VERSION 5.7 ;
  NOWIREEXTENSIONATPIN ON ;
  DIVIDERCHAR "/" ;
  BUSBITCHARS "[]" ;
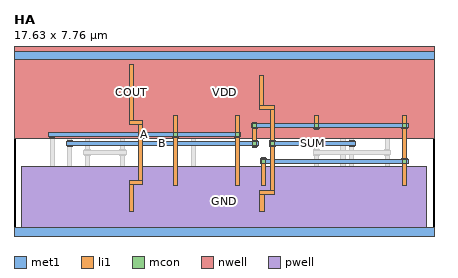
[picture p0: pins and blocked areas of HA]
MACRO HA
  CLASS CORE ;
  FOREIGN HA ;
  ORIGIN 0.000 0.000 ;
  SIZE 17.630 BY 7.760 ;
  SYMMETRY X Y ;
  SITE unitrh ;
  PIN SUM
    DIRECTION OUTPUT ;
    USE SIGNAL ;
    ANTENNADIFFAREA 1.543800 ;
    PORT
      LAYER met1 ;
        RECT 10.735 3.965 10.965 3.995 ;
        RECT 14.065 3.965 14.295 3.995 ;
        RECT 10.705 3.795 14.325 3.965 ;
        RECT 10.735 3.765 10.965 3.795 ;
        RECT 14.065 3.765 14.295 3.795 ;
    END
    PORT
      LAYER li1 ;
        RECT 10.285 5.470 10.455 6.740 ;
        RECT 10.285 5.300 10.935 5.470 ;
        RECT 10.765 1.920 10.935 5.300 ;
        RECT 10.325 1.750 10.935 1.920 ;
        RECT 10.325 1.020 10.495 1.750 ;
      LAYER mcon ;
        RECT 10.765 3.795 10.935 3.965 ;
    END
  END SUM
  PIN COUT
    DIRECTION OUTPUT ;
    USE SIGNAL ;
    ANTENNADIFFAREA 0.771900 ;
    PORT
      LAYER li1 ;
        RECT 4.850 4.845 5.020 7.200 ;
        RECT 4.850 4.675 5.385 4.845 ;
        RECT 5.215 2.345 5.385 4.675 ;
        RECT 4.845 2.175 5.385 2.345 ;
        RECT 4.845 1.020 5.015 2.175 ;
    END
  END COUT
  PIN A
    DIRECTION INPUT ;
    USE SIGNAL ;
    ANTENNAGATEAREA 3.093750 ;
    PORT
      LAYER met1 ;
        RECT 1.485 4.335 1.715 4.365 ;
        RECT 6.665 4.335 6.895 4.365 ;
        RECT 9.255 4.335 9.485 4.365 ;
        RECT 1.455 4.165 9.515 4.335 ;
        RECT 1.485 4.135 1.715 4.165 ;
        RECT 6.665 4.135 6.895 4.165 ;
        RECT 9.255 4.135 9.485 4.165 ;
    END
    PORT
      LAYER li1 ;
        RECT 6.695 2.100 6.865 5.045 ;
      LAYER mcon ;
        RECT 6.695 4.165 6.865 4.335 ;
    END
    PORT
      LAYER li1 ;
        RECT 9.285 2.100 9.455 5.045 ;
      LAYER mcon ;
        RECT 9.285 4.165 9.455 4.335 ;
    END
  END A
  PIN B
    DIRECTION INPUT ;
    USE SIGNAL ;
    ANTENNAGATEAREA 3.081750 ;
    PORT
      LAYER met1 ;
        RECT 9.995 4.705 10.225 4.735 ;
        RECT 12.585 4.705 12.815 4.735 ;
        RECT 16.285 4.705 16.515 4.735 ;
        RECT 9.965 4.535 16.545 4.705 ;
        RECT 9.995 4.505 10.225 4.535 ;
        RECT 12.585 4.505 12.815 4.535 ;
        RECT 16.285 4.505 16.515 4.535 ;
        RECT 2.225 3.965 2.455 3.995 ;
        RECT 9.995 3.965 10.225 3.995 ;
        RECT 2.195 3.795 10.255 3.965 ;
        RECT 2.225 3.765 2.455 3.795 ;
        RECT 9.995 3.765 10.225 3.795 ;
        RECT 10.365 3.225 10.595 3.255 ;
        RECT 16.285 3.225 16.515 3.255 ;
        RECT 10.335 3.055 16.545 3.225 ;
        RECT 10.365 3.025 10.595 3.055 ;
        RECT 16.285 3.025 16.515 3.055 ;
    END
    PORT
      LAYER li1 ;
        RECT 10.025 3.715 10.195 4.785 ;
      LAYER mcon ;
        RECT 10.025 4.535 10.195 4.705 ;
        RECT 10.025 3.795 10.195 3.965 ;
    END
    PORT
      LAYER li1 ;
        RECT 10.395 2.100 10.565 3.305 ;
      LAYER mcon ;
        RECT 10.395 3.055 10.565 3.225 ;
    END
    PORT
      LAYER li1 ;
        RECT 16.315 2.100 16.485 5.045 ;
      LAYER mcon ;
        RECT 16.315 4.535 16.485 4.705 ;
        RECT 16.315 3.055 16.485 3.225 ;
    END
    PORT
      LAYER li1 ;
        RECT 12.615 4.455 12.785 5.045 ;
      LAYER mcon ;
        RECT 12.615 4.535 12.785 4.705 ;
    END
  END B
  PIN VDD
    DIRECTION INOUT ;
    USE POWER ;
    SHAPE ABUTMENT ;
    PORT
      LAYER nwell ;
        RECT 0.000 4.110 17.630 7.940 ;
      LAYER met1 ;
        RECT 0.000 7.410 17.630 7.760 ;
    END
  END VDD
  PIN GND
    DIRECTION INOUT ;
    USE GROUND ;
    SHAPE ABUTMENT ;
    PORT
      LAYER pwell ;
        RECT 0.320 0.000 17.310 2.900 ;
      LAYER met1 ;
        RECT 0.000 0.000 17.630 0.350 ;
    END
  END GND
  OBS
      LAYER li1 ;
        RECT 0.000 7.410 17.630 7.760 ;
        RECT 0.320 4.290 0.660 7.410 ;
        RECT 1.195 5.315 1.365 7.410 ;
        RECT 1.635 5.465 1.805 7.200 ;
        RECT 2.075 5.735 2.245 7.410 ;
        RECT 2.515 5.465 2.685 7.200 ;
        RECT 2.955 5.735 3.125 7.410 ;
        RECT 1.635 5.295 3.165 5.465 ;
        RECT 0.320 0.350 0.660 2.900 ;
        RECT 1.515 2.095 1.685 5.045 ;
        RECT 2.285 4.890 2.455 5.045 ;
        RECT 2.255 4.715 2.455 4.890 ;
        RECT 2.255 2.095 2.425 4.715 ;
        RECT 1.100 1.845 1.270 1.925 ;
        RECT 2.070 1.845 2.240 1.925 ;
        RECT 2.995 1.920 3.165 5.295 ;
        RECT 3.650 4.290 3.990 7.410 ;
        RECT 4.410 5.365 4.580 7.410 ;
        RECT 5.290 5.365 5.460 7.410 ;
        RECT 1.100 1.675 2.240 1.845 ;
        RECT 1.100 0.545 1.270 1.675 ;
        RECT 1.585 0.350 1.755 1.300 ;
        RECT 2.070 0.795 2.240 1.675 ;
        RECT 2.555 1.750 3.165 1.920 ;
        RECT 2.555 1.015 2.725 1.750 ;
        RECT 3.040 0.795 3.210 1.565 ;
        RECT 2.070 0.625 3.210 0.795 ;
        RECT 2.070 0.545 2.240 0.625 ;
        RECT 3.040 0.545 3.210 0.625 ;
        RECT 3.650 0.350 3.990 2.900 ;
        RECT 4.475 2.100 4.645 5.045 ;
        RECT 5.870 4.290 6.210 7.410 ;
        RECT 6.630 5.365 6.800 7.410 ;
        RECT 7.070 4.845 7.240 7.200 ;
        RECT 7.510 5.365 7.680 7.410 ;
        RECT 7.070 4.675 7.605 4.845 ;
        RECT 4.365 0.800 4.535 1.930 ;
        RECT 5.335 0.800 5.505 1.930 ;
        RECT 4.365 0.630 5.505 0.800 ;
        RECT 4.365 0.350 4.535 0.630 ;
        RECT 4.850 0.350 5.020 0.630 ;
        RECT 5.335 0.350 5.505 0.630 ;
        RECT 5.870 0.350 6.210 2.900 ;
        RECT 7.435 2.345 7.605 4.675 ;
        RECT 8.090 4.290 8.430 7.410 ;
        RECT 8.965 5.470 9.135 7.080 ;
        RECT 9.405 5.730 9.575 7.410 ;
        RECT 9.845 7.000 10.895 7.170 ;
        RECT 9.845 5.470 10.015 7.000 ;
        RECT 10.725 5.730 10.895 7.000 ;
        RECT 8.965 5.300 10.015 5.470 ;
        RECT 10.395 4.085 10.565 5.045 ;
        RECT 11.420 4.290 11.760 7.410 ;
        RECT 12.295 5.470 12.465 7.080 ;
        RECT 12.735 5.730 12.905 7.410 ;
        RECT 13.175 7.000 14.225 7.170 ;
        RECT 13.175 5.470 13.345 7.000 ;
        RECT 12.295 5.300 13.345 5.470 ;
        RECT 13.615 5.470 13.785 6.740 ;
        RECT 14.055 5.730 14.225 7.000 ;
        RECT 13.615 5.300 14.265 5.470 ;
        RECT 7.065 2.175 7.605 2.345 ;
        RECT 6.585 0.800 6.755 1.930 ;
        RECT 7.065 1.020 7.235 2.175 ;
        RECT 7.555 0.800 7.725 1.930 ;
        RECT 6.585 0.630 7.725 0.800 ;
        RECT 6.585 0.350 6.755 0.630 ;
        RECT 7.070 0.350 7.240 0.630 ;
        RECT 7.555 0.350 7.725 0.630 ;
        RECT 8.090 0.350 8.430 2.900 ;
        RECT 8.870 1.850 9.040 1.930 ;
        RECT 9.840 1.850 10.010 1.930 ;
        RECT 8.870 1.680 10.010 1.850 ;
        RECT 8.870 0.550 9.040 1.680 ;
        RECT 9.355 0.350 9.525 1.305 ;
        RECT 9.840 0.800 10.010 1.680 ;
        RECT 10.810 0.800 10.980 1.570 ;
        RECT 9.840 0.630 10.980 0.800 ;
        RECT 9.840 0.550 10.010 0.630 ;
        RECT 10.810 0.550 10.980 0.630 ;
        RECT 11.420 0.350 11.760 2.900 ;
        RECT 12.615 2.100 12.785 3.675 ;
        RECT 13.725 2.100 13.895 5.045 ;
        RECT 12.200 1.850 12.370 1.930 ;
        RECT 13.170 1.850 13.340 1.930 ;
        RECT 14.095 1.920 14.265 5.300 ;
        RECT 14.750 4.290 15.090 7.410 ;
        RECT 15.500 5.365 15.670 7.410 ;
        RECT 15.940 4.845 16.110 7.200 ;
        RECT 16.380 5.365 16.550 7.410 ;
        RECT 15.575 4.675 16.110 4.845 ;
        RECT 12.200 1.680 13.340 1.850 ;
        RECT 12.200 0.550 12.370 1.680 ;
        RECT 12.685 0.350 12.855 1.305 ;
        RECT 13.170 0.800 13.340 1.680 ;
        RECT 13.655 1.750 14.265 1.920 ;
        RECT 13.655 1.020 13.825 1.750 ;
        RECT 14.140 0.800 14.310 1.570 ;
        RECT 13.170 0.630 14.310 0.800 ;
        RECT 13.170 0.550 13.340 0.630 ;
        RECT 14.140 0.550 14.310 0.630 ;
        RECT 14.750 0.350 15.090 2.900 ;
        RECT 15.575 2.345 15.745 4.675 ;
        RECT 16.970 4.290 17.310 7.410 ;
        RECT 15.575 2.175 16.115 2.345 ;
        RECT 15.455 0.800 15.625 1.930 ;
        RECT 15.945 1.020 16.115 2.175 ;
        RECT 16.425 0.800 16.595 1.930 ;
        RECT 15.455 0.630 16.595 0.800 ;
        RECT 15.455 0.350 15.625 0.630 ;
        RECT 15.940 0.350 16.110 0.630 ;
        RECT 16.425 0.350 16.595 0.630 ;
        RECT 16.970 0.350 17.310 2.900 ;
        RECT 0.000 0.000 17.630 0.350 ;
      LAYER mcon ;
        RECT 0.775 7.495 0.945 7.665 ;
        RECT 1.145 7.495 1.315 7.665 ;
        RECT 1.515 7.495 1.685 7.665 ;
        RECT 1.885 7.495 2.055 7.665 ;
        RECT 2.255 7.495 2.425 7.665 ;
        RECT 2.625 7.495 2.795 7.665 ;
        RECT 2.995 7.495 3.165 7.665 ;
        RECT 3.365 7.495 3.535 7.665 ;
        RECT 4.105 7.495 4.275 7.665 ;
        RECT 4.475 7.495 4.645 7.665 ;
        RECT 4.845 7.495 5.015 7.665 ;
        RECT 5.215 7.495 5.385 7.665 ;
        RECT 5.585 7.495 5.755 7.665 ;
        RECT 6.325 7.495 6.495 7.665 ;
        RECT 6.695 7.495 6.865 7.665 ;
        RECT 7.065 7.495 7.235 7.665 ;
        RECT 7.435 7.495 7.605 7.665 ;
        RECT 7.805 7.495 7.975 7.665 ;
        RECT 8.545 7.495 8.715 7.665 ;
        RECT 8.915 7.495 9.085 7.665 ;
        RECT 9.285 7.495 9.455 7.665 ;
        RECT 9.655 7.495 9.825 7.665 ;
        RECT 10.025 7.495 10.195 7.665 ;
        RECT 10.395 7.495 10.565 7.665 ;
        RECT 10.765 7.495 10.935 7.665 ;
        RECT 11.135 7.495 11.305 7.665 ;
        RECT 11.875 7.495 12.045 7.665 ;
        RECT 12.245 7.495 12.415 7.665 ;
        RECT 12.615 7.495 12.785 7.665 ;
        RECT 12.985 7.495 13.155 7.665 ;
        RECT 13.355 7.495 13.525 7.665 ;
        RECT 13.725 7.495 13.895 7.665 ;
        RECT 14.095 7.495 14.265 7.665 ;
        RECT 14.465 7.495 14.635 7.665 ;
        RECT 15.205 7.495 15.375 7.665 ;
        RECT 15.575 7.495 15.745 7.665 ;
        RECT 15.945 7.495 16.115 7.665 ;
        RECT 16.315 7.495 16.485 7.665 ;
        RECT 16.685 7.495 16.855 7.665 ;
        RECT 1.515 4.165 1.685 4.335 ;
        RECT 2.255 3.795 2.425 3.965 ;
        RECT 2.995 3.425 3.165 3.595 ;
        RECT 4.475 3.425 4.645 3.595 ;
        RECT 10.395 4.165 10.565 4.335 ;
        RECT 12.615 3.425 12.785 3.595 ;
        RECT 7.435 2.685 7.605 2.855 ;
        RECT 13.725 2.685 13.895 2.855 ;
        RECT 14.095 3.795 14.265 3.965 ;
        RECT 15.575 4.165 15.745 4.335 ;
        RECT 15.575 3.425 15.745 3.595 ;
        RECT 0.775 0.095 0.945 0.265 ;
        RECT 1.145 0.095 1.315 0.265 ;
        RECT 1.515 0.095 1.685 0.265 ;
        RECT 1.885 0.095 2.055 0.265 ;
        RECT 2.255 0.095 2.425 0.265 ;
        RECT 2.625 0.095 2.795 0.265 ;
        RECT 2.995 0.095 3.165 0.265 ;
        RECT 3.365 0.095 3.535 0.265 ;
        RECT 4.105 0.095 4.275 0.265 ;
        RECT 4.475 0.095 4.645 0.265 ;
        RECT 4.845 0.095 5.015 0.265 ;
        RECT 5.215 0.095 5.385 0.265 ;
        RECT 5.585 0.095 5.755 0.265 ;
        RECT 6.325 0.095 6.495 0.265 ;
        RECT 6.695 0.095 6.865 0.265 ;
        RECT 7.065 0.095 7.235 0.265 ;
        RECT 7.435 0.095 7.605 0.265 ;
        RECT 7.805 0.095 7.975 0.265 ;
        RECT 8.545 0.095 8.715 0.265 ;
        RECT 8.915 0.095 9.085 0.265 ;
        RECT 9.285 0.095 9.455 0.265 ;
        RECT 9.655 0.095 9.825 0.265 ;
        RECT 10.025 0.095 10.195 0.265 ;
        RECT 10.395 0.095 10.565 0.265 ;
        RECT 10.765 0.095 10.935 0.265 ;
        RECT 11.135 0.095 11.305 0.265 ;
        RECT 11.875 0.095 12.045 0.265 ;
        RECT 12.245 0.095 12.415 0.265 ;
        RECT 12.615 0.095 12.785 0.265 ;
        RECT 12.985 0.095 13.155 0.265 ;
        RECT 13.355 0.095 13.525 0.265 ;
        RECT 13.725 0.095 13.895 0.265 ;
        RECT 14.095 0.095 14.265 0.265 ;
        RECT 14.465 0.095 14.635 0.265 ;
        RECT 15.205 0.095 15.375 0.265 ;
        RECT 15.575 0.095 15.745 0.265 ;
        RECT 15.945 0.095 16.115 0.265 ;
        RECT 16.315 0.095 16.485 0.265 ;
        RECT 16.685 0.095 16.855 0.265 ;
      LAYER met1 ;
        RECT 10.365 4.335 10.595 4.365 ;
        RECT 15.545 4.335 15.775 4.365 ;
        RECT 10.335 4.165 15.805 4.335 ;
        RECT 10.365 4.135 10.595 4.165 ;
        RECT 15.545 4.135 15.775 4.165 ;
        RECT 2.965 3.595 3.195 3.625 ;
        RECT 4.445 3.595 4.675 3.625 ;
        RECT 12.585 3.595 12.815 3.625 ;
        RECT 15.545 3.595 15.775 3.625 ;
        RECT 2.935 3.425 4.705 3.595 ;
        RECT 12.555 3.425 15.805 3.595 ;
        RECT 2.965 3.395 3.195 3.425 ;
        RECT 4.445 3.395 4.675 3.425 ;
        RECT 12.585 3.395 12.815 3.425 ;
        RECT 15.545 3.395 15.775 3.425 ;
        RECT 7.405 2.855 7.635 2.885 ;
        RECT 13.695 2.855 13.925 2.885 ;
        RECT 7.375 2.685 13.955 2.855 ;
        RECT 7.405 2.655 7.635 2.685 ;
        RECT 13.695 2.655 13.925 2.685 ;
  END
END HA
END LIBRARY

